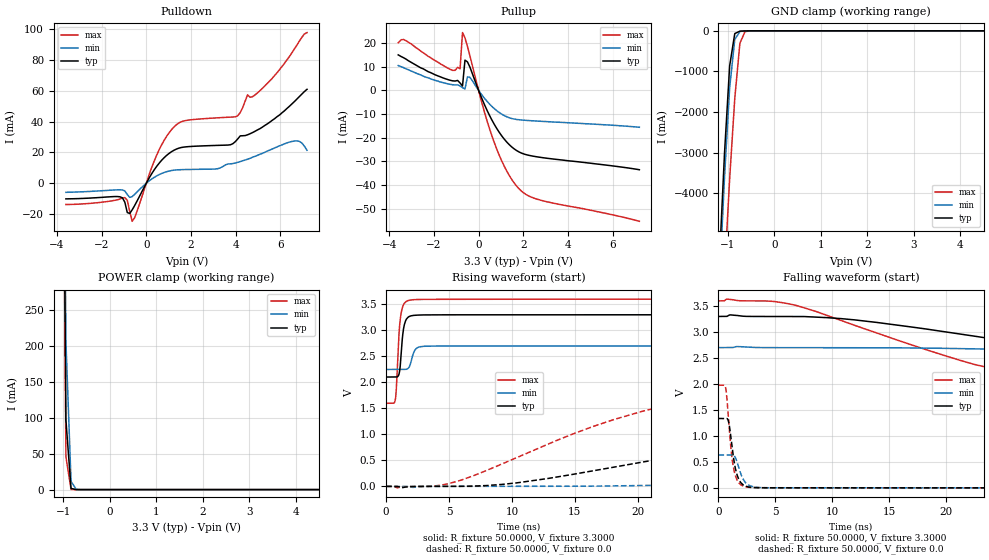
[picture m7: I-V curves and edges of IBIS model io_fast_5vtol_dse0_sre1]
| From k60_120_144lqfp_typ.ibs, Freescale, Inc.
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[Model]  io_fast_5vtol_dse0_sre1
|   Model io_fast_5vtol_dse0_sre1
| Library cells for typ/min/max conditions are connected as defined below:
|  pad - External Pad
|  ipp_do - Core Input
|  ipp_obe - Output Buffer Enable
|  esd_boost - vdd_s_3v
|  esd_bus - vdd_s_3v
|  ipp_ame - vss_s_lv
|  ipp_dse - vss_s_lv
|  ipp_ina40a_5vtol - NC
|  ipp_ina40b_5vtol - NC
|  ipp_ina_5vtol - NC
|  ipp_ina_mux_3v - NC
|  ipp_ind - NC
|  ipp_ind_3v - NC
|  ipp_pue - vss_s_lv
|  ipp_sre - vdd_s_lv
|  tie_3v - vdd_s_3v
|  tie_hi - vdd_s_lv
|  vbuf_3v - vdd_s_3v
|  vdd_bulk_lv - vdd_s_lv
|  vdd_s_3v - vdd_s_3v
|  vdd_s_lv - vdd_s_lv
|  vss_bulk - vss_s_3v
|  vss_s_3v - vss_s_3v
|  vss_s_lv - vss_s_lv
| All other pins connected to ground
Model_type I/O
Polarity   Non-Inverting
Enable   Active-High
Vinl =   1.1550V
Vinh =   2.3100V
Vmeas =  1.6500V
Cref =   25.0000pF
Rref =   50.0000
Vref =   0.0V
C_comp   4.8314pF   4.6080pF   5.0799pF
[Temperature Range]   25.0000   0.1250k   -40.0000
[Voltage Range]   3.3000V   2.7000V   3.6000V
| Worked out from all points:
|   slope of the pulldown table from 0 to 0.495 V, typ, clamps not added: 43 ohm
|   slope of the pullup table from 0 to 0.495 V, typ, clamps not added: 46.1 ohm
|   GND clamp passes 1 mA (typ) near -0.54 V on its own axis
|   POWER clamp passes 1 mA (typ) near -0.79 V on its own axis
|   rising waveform, R_fixture 50.0000, V_fixture 3.3000: 20-80 % time 278ps typ, 356ps min, 278ps max; typ from 2.1 V to 3.3 V
|   rising waveform, R_fixture 50.0000, V_fixture 0.0: 20-80 % time 24.1ns typ, 43.5ns min, 14ns max; typ from 0 V to 1.33 V
|   falling waveform, R_fixture 50.0000, V_fixture 3.3000: 20-80 % time 27.2ns typ, 45.7ns min, 19.1ns max; typ from 3.3 V to 2.1 V
|   falling waveform, R_fixture 50.0000, V_fixture 0.0: 20-80 % time 572ps typ, 678ps min, 522ps max; typ from 1.33 V to 0 V
[Pulldown]
|Voltage   I(typ)   I(min)   I(max)
-3.6V     -10.1mA    -5.85mA    -13.73mA
-1.29V    -8.593mA   -4.245mA   -10.67mA
-960mV    -12.21mA   -4.926mA   -9.278mA
-850mV    -18.97mA   -7.293mA   -11mA
-630mV    -17.18mA   -8.599mA   -24.63mA
470mV     11.04mA    4.829mA    18.36mA
1.24V     21.41mA    8.514mA    36.48mA
4.1V      28.81mA    13.6mA     43.8mA
4.54V     31.46mA    15.6mA     57.37mA
5.2V      36.4mA     19.4mA     61.5mA
6.63V     52.9mA     27.4mA     87mA
7.2V      60.9mA     21.4mA     97.7mA
[Pullup]
|Voltage   I(typ)   I(min)   I(max)
-3.6V     15mA       10.5mA     20.1mA
-3.25V    13.2mA     9.1mA      21mA
-1.05V    3.94mA     2.29mA     8.456mA
-830mV    3.101mA    1.841mA    9.14mA
-720mV    1.84mA     1.154mA    24.43mA
-610mV    12.78mA    580.6uA    22.17mA
-500mV    12.05mA    5.655mA    18.59mA
710mV     -14.5mA    -7.801mA   -22.29mA
1.26V     -21.86mA   -11.17mA   -34.13mA
1.81V     -26.05mA   -12.44mA   -41.62mA
2.8V      -28.38mA   -13.1mA    -46.51mA
7.2V      -33.58mA   -15.62mA   -55.39mA
[GND_clamp]
|Voltage   I(typ)   I(min)   I(max)
-3.6V     -73.34A    -73.38A    -74.77A
-1.18V    -5.66A     -6.206A    -8.642A
-1.07V    -2.998A    -3.593A    -5.955A
-960mV    -859.3mA   -1.399A    -3.637A
-850mV    -67.61mA   -213.2mA   -1.663A
-740mV    -7.668mA   -16.88mA   -304.8mA
-630mV    -2.587mA   -2.229mA   -18.83mA
-520mV    -662.1uA   -532.3uA   -1.741mA
7.2V      0A         0A         0A
[POWER_clamp]
|Voltage   I(typ)   I(min)   I(max)
-3.6V     45.85A     45.45A     46.17A
-1.05V    1.004A     1.14A      941.6mA
-940mV    96.57mA    206.1mA    45.73mA
-830mV    1.646mA    11.48mA    218.1uA
-720mV    22.84uA    474.3uA    919.1nA
-610mV    316.6nA    19.24uA    4.178nA
7.2V      0A         0A         0A
[Ramp]
| variable   typ   min   max
dV/dt_r  0.8012/24.0524n   0.3796/43.5161n   1.1861/13.9678n
dV/dt_f  0.7188/27.2464n   0.2707/45.7505n   1.2016/19.1270n
R_load = 50.0000
[Rising Waveform]
R_fixture= 50.0000
V_fixture= 3.3000
V_fixture_min= 2.7000
V_fixture_max= 3.6000
|time   V(typ)   V(min)   V(max)
0s        2.102V     2.248V     1.597V
731.6ps   2.103V     2.248V     1.669V
802ps     2.103V     2.248V     1.848V
992.4ps   2.139V     2.248V     2.819V
1.066ns   2.206V     2.248V     3.081V
1.26ns    2.772V     2.249V     3.415V
1.381ns   3.03V      2.249V     3.493V
1.614ns   3.218V     2.252V     3.557V
2.344ns   3.291V     2.637V     3.592V
250ns     3.3V       2.7V       3.6V
[Rising Waveform]
R_fixture= 50.0000
V_fixture= 0.0
V_fixture_min= 0.0
V_fixture_max= 0.0
|time   V(typ)   V(min)   V(max)
0s        1.032nV    103.3nV    632.6pV
3.849ns   -568.3uV   -420.3uV   8.023mV
5.922ns   1.102mV    -220.5uV   117mV
16.39ns   296.4mV    4.032mV    1.147V
22.46ns   554.7mV    27.59mV    1.565V
29.22ns   807.4mV    80.7mV     1.802V
37.72ns   1.028V     169.5mV    1.913V
56.47ns   1.257V     366.1mV    1.969V
100.2ns   1.332V     581.3mV    1.977V
250ns     1.335V     632.7mV    1.977V
[Falling Waveform]
R_fixture= 50.0000
V_fixture= 3.3000
V_fixture_min= 2.7000
V_fixture_max= 3.6000
|time   V(typ)   V(min)   V(max)
0s        3.3V       2.7V       3.6V
4.035ns   3.3V       2.7V       3.6V
6.92ns    3.299V     2.7V       3.507V
21.28ns   2.961V     2.681V     2.453V
28.06ns   2.739V     2.651V     2.083V
36.08ns   2.505V     2.6V       1.839V
44.45ns   2.354V     2.536V     1.731V
62.23ns   2.21V      2.41V      1.643V
90.73ns   2.134V     2.316V     1.607V
250ns     2.102V     2.249V     1.597V
[Falling Waveform]
R_fixture= 50.0000
V_fixture= 0.0
V_fixture_min= 0.0
V_fixture_max= 0.0
|time   V(typ)   V(min)   V(max)
0s        1.335V     632.8mV    1.977V
632.1ps   1.334V     632.8mV    1.924V
733.6ps   1.335V     632.8mV    1.742V
883.6ps   1.278V     632.8mV    1.315V
1.142ns   876mV      632.1mV    655.6mV
1.475ns   384.5mV    587.3mV    241.5mV
1.785ns   162.1mV    384.5mV    97.61mV
2.187ns   55.75mV    159.7mV    31.38mV
3.128ns   5.99mV     17.62mV    4.124mV
250ns     39.33nV    2.59uV     8.922nV
